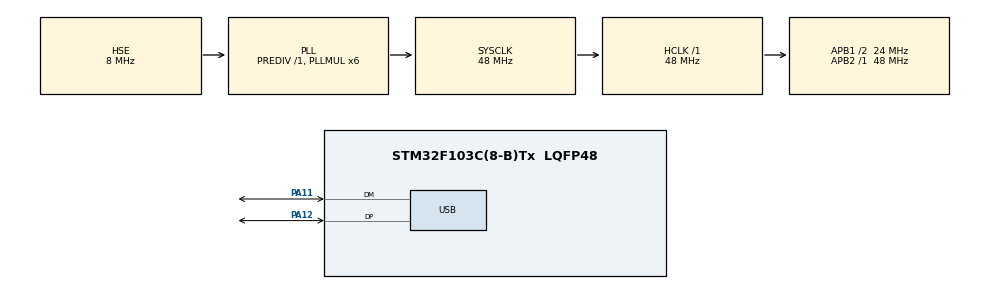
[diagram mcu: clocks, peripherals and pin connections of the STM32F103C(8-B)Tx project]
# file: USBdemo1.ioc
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Mcu.Family=STM32F1
Mcu.Name=STM32F103C(8-B)Tx
Mcu.Package=LQFP48
NVIC.PriorityGroup=NVIC_PRIORITYGROUP_4
NVIC.USB_LP_CAN1_RX0_IRQn=true\:0\:0\:false\:false\:true\:false\:true\:true
PA11.Mode=Device
PA11.Signal=USB_DM
PA12.Mode=Device
PA12.Signal=USB_DP
PA13.Mode=Serial_Wire
PA13.Signal=SYS_JTMS-SWDIO
PA14.Mode=Serial_Wire
PA14.Signal=SYS_JTCK-SWCLK
PD0-OSC_IN.Mode=HSE-External-Oscillator
PD0-OSC_IN.Signal=RCC_OSC_IN
PD1-OSC_OUT.Mode=HSE-External-Oscillator
PD1-OSC_OUT.Signal=RCC_OSC_OUT
ProjectManager.HeapSize=0x200
ProjectManager.StackSize=0x400
ProjectManager.TargetToolchain=MDK-ARM V5.32
RCC.AHBFreq_Value=48000000
RCC.APB1CLKDivider=RCC_HCLK_DIV2
RCC.APB1Freq_Value=24000000
RCC.APB1TimFreq_Value=48000000
RCC.APB2Freq_Value=48000000
RCC.APB2TimFreq_Value=48000000
RCC.HCLKFreq_Value=48000000
RCC.PLLMUL=RCC_PLL_MUL6
RCC.PLLSourceVirtual=RCC_PLLSOURCE_HSE
RCC.SYSCLKFreq_VALUE=48000000
RCC.SYSCLKSource=RCC_SYSCLKSOURCE_PLLCLK
RCC.USBFreq_Value=48000000
USB_DEVICE.CLASS_NAME_FS=HID
USB_DEVICE.VirtualMode=Hid
USB_DEVICE.VirtualModeFS=Hid_FS
VP_USB_DEVICE_VS_USB_DEVICE_HID_FS.Mode=HID_FS
board=custom

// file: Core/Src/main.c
/* USER CODE BEGIN Header */
/**
  ******************************************************************************
  * @file           : main.c
  * @brief          : Main program body
  ******************************************************************************
  * @attention
  *
  * Copyright (c) 2023 STMicroelectronics.
  * All rights reserved.
  *
  * This software is licensed under terms that can be found in the LICENSE file
  * in the root directory of this software component.
  * If no LICENSE file comes with this software, it is provided AS-IS.
  *
  ******************************************************************************
  */
/* USER CODE END Header */
#include "main.h"
#include "usb_device.h"
#include "gpio.h"

#include "usbd_hid.h"
/* USER CODE BEGIN PTD */
uint8_t MouseData1[4] = {0,0,0,0};
unsigned char keyNum = 0;

extern USBD_HandleTypeDef hUsbDeviceFS;
extern uint8_t USBD_HID_SendReport(USBD_HandleTypeDef *pdev,
	                       uint8_t *report,
                           uint16_t len);

//构造一个鼠标事件
typedef struct{
	char mouse_abs_left : 1;  //左键单击
	char mouse_abs_right : 1;  //右键单机
	char mouse_abs_wheel : 1;  //中键单击
	char reserve : 5;  //常量0
	char mouse_rel_x;  //鼠标x轴移动
	char mouse_rel_y;  //鼠标y轴移动
	char mouse_rel_wheel;  //鼠标滚轮移动值
}tyMouse_buf;

/* USER CODE END PTD */

#define KEY0_Press (1<<0)
#define KEY1_Press (1<<1)
#define KEY2_Press (1<<2)
#define KEY3_Press (1<<3)

tyMouse_buf tMouse_buff;

void User_init(void)
{
	tMouse_buff.mouse_abs_left = 0;
	tMouse_buff.mouse_abs_right = 0;
	tMouse_buff.mouse_abs_wheel = 0;
	tMouse_buff.reserve = 0;
	tMouse_buff.mouse_rel_x = 0;
	tMouse_buff.mouse_rel_y = 0;
	tMouse_buff.mouse_rel_wheel = 0;
}
/* USER CODE BEGIN PD */

//读取Key的按键值
unsigned char Get_key_num(void)
{
	if(HAL_GPIO_ReadPin(GPIOB,GPIO_PIN_1)==0)
	{
		HAL_Delay(20); //按键消抖操作
		while(HAL_GPIO_ReadPin(GPIOB,GPIO_PIN_1)==0);
		HAL_Delay(20);
		keyNum = 1;
	}
	if(HAL_GPIO_ReadPin(GPIOB,GPIO_PIN_11)==0)
	{
		HAL_Delay(20);
		while(HAL_GPIO_ReadPin(GPIOB,GPIO_PIN_11)==0);
		HAL_Delay(20);
		keyNum = 2;
	}

	return keyNum;
}

void Send_mouse_msg(void)
{
	USBD_HID_SendReport(&hUsbDeviceFS,(uint8_t *)&tMouse_buff,sizeof(tMouse_buff));
}
/* USER CODE END PD */

void SystemClock_Config(void);
static void MX_GPIO_Init(void);

int main(void)
{

  //unsigned char keyNumLast;
  //int cnt;
  /* MCU Configuration--------------------------------------------------------*/

  /* Reset of all peripherals, Initializes the Flash interface and the Systick. */
  HAL_Init();

  /* Configure the system clock */
  SystemClock_Config();

  /* Initialize all configured peripherals */
  MX_GPIO_Init();
  MX_USB_DEVICE_Init();

  /* Infinite loop */
  /* USER CODE BEGIN WHILE */
  while (1)
  {
	  keyNum = Get_key_num();
    if(keyNum == 1)
	{
		MouseData1[0] = 0x02; //鼠标右键按下
		USBD_HID_SendReport(&hUsbDeviceFS,(uint8_t*)&MouseData1,sizeof(MouseData1));
	}
    if(keyNum == 2)
	{
		MouseData1[0]=0x01; //鼠标左键按下
	   USBD_HID_SendReport(&hUsbDeviceFS,(uint8_t*)&MouseData1,sizeof(MouseData1));
	}
  }

}

void SystemClock_Config(void)
{
  RCC_OscInitTypeDef RCC_OscInitStruct = {0};
  RCC_ClkInitTypeDef RCC_ClkInitStruct = {0};
  RCC_PeriphCLKInitTypeDef PeriphClkInit = {0};

  /** Initializes the RCC Oscillators according to the specified parameters
  * in the RCC_OscInitTypeDef structure.
  */
  RCC_OscInitStruct.OscillatorType = RCC_OSCILLATORTYPE_HSE;
  RCC_OscInitStruct.HSEState = RCC_HSE_ON;
  RCC_OscInitStruct.HSEPredivValue = RCC_HSE_PREDIV_DIV1;
  RCC_OscInitStruct.HSIState = RCC_HSI_ON;
  RCC_OscInitStruct.PLL.PLLState = RCC_PLL_ON;
  RCC_OscInitStruct.PLL.PLLSource = RCC_PLLSOURCE_HSE;
  RCC_OscInitStruct.PLL.PLLMUL = RCC_PLL_MUL6;
  if (HAL_RCC_OscConfig(&RCC_OscInitStruct) != HAL_OK)
  {
    Error_Handler();
  }

  /** Initializes the CPU, AHB and APB buses clocks
  */
  RCC_ClkInitStruct.ClockType = RCC_CLOCKTYPE_HCLK|RCC_CLOCKTYPE_SYSCLK
                              |RCC_CLOCKTYPE_PCLK1|RCC_CLOCKTYPE_PCLK2;
  RCC_ClkInitStruct.SYSCLKSource = RCC_SYSCLKSOURCE_PLLCLK;
  RCC_ClkInitStruct.AHBCLKDivider = RCC_SYSCLK_DIV1;
  RCC_ClkInitStruct.APB1CLKDivider = RCC_HCLK_DIV2;
  RCC_ClkInitStruct.APB2CLKDivider = RCC_HCLK_DIV1;

  if (HAL_RCC_ClockConfig(&RCC_ClkInitStruct, FLASH_LATENCY_1) != HAL_OK)
  {
    Error_Handler();
  }
  PeriphClkInit.PeriphClockSelection = RCC_PERIPHCLK_USB;
  PeriphClkInit.UsbClockSelection = RCC_USBCLKSOURCE_PLL;
  if (HAL_RCCEx_PeriphCLKConfig(&PeriphClkInit) != HAL_OK)
  {
    Error_Handler();
  }
}

static void MX_GPIO_Init(void)
{
	GPIO_InitTypeDef GPIO_InitStruct = {0};

	//GPIO 接口时钟使能
	__HAL_RCC_GPIOE_CLK_ENABLE();
	__HAL_RCC_GPIOB_CLK_ENABLE();

	//配置GPIO 接口：B11 B1
	GPIO_InitStruct.Pin = GPIO_PIN_1 | GPIO_PIN_11;
	GPIO_InitStruct.Mode = GPIO_MODE_INPUT;
	GPIO_InitStruct.Pull = GPIO_PULLUP;
	HAL_GPIO_Init(GPIOE,&GPIO_InitStruct);
}

void Error_Handler(void)
{
  __disable_irq();
  while (1)
  {
  }
}
